One B-rep face of a CAD part: STEP entity #61270.
In plain terms, the planar face has unit normal (0, 0, -1).
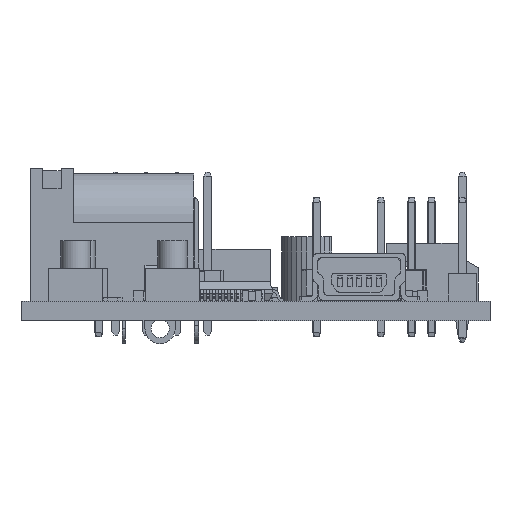
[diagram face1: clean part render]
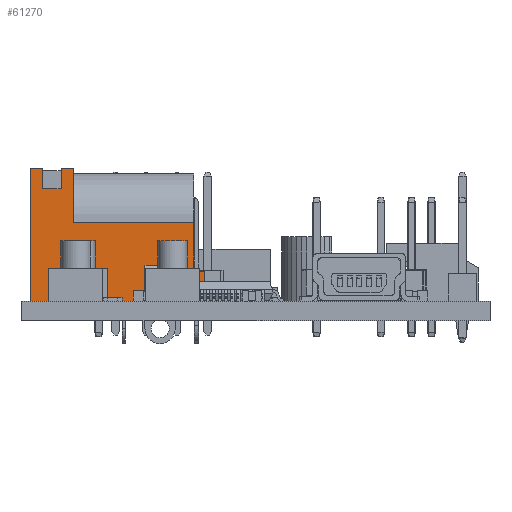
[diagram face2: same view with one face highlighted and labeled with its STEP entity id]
Its self-contained STEP definition (entity closure, numbers rounded to 3 decimals):
#61107 = VERTEX_POINT('',#61108);
#61108 = CARTESIAN_POINT('',(-14.4,-6.5,-4.5));
#61114 = EDGE_CURVE('',#61107,#61115,#61117,.T.);
#61115 = VERTEX_POINT('',#61116);
#61116 = CARTESIAN_POINT('',(-11.95,-6.5,-4.5));
#61117 = LINE('',#61118,#61119);
#61118 = CARTESIAN_POINT('',(-14.4,-6.5,-4.5));
#61119 = VECTOR('',#61120,1.);
#61120 = DIRECTION('',(1.,0.,0.));
#61123 = VERTEX_POINT('',#61124);
#61124 = CARTESIAN_POINT('',(-9.45,-6.5,-4.5));
#61130 = EDGE_CURVE('',#61123,#61131,#61133,.T.);
#61131 = VERTEX_POINT('',#61132);
#61132 = CARTESIAN_POINT('',(0.,-6.5,-4.5));
#61133 = LINE('',#61134,#61135);
#61134 = CARTESIAN_POINT('',(-14.4,-6.5,-4.5));
#61135 = VECTOR('',#61136,1.);
#61136 = DIRECTION('',(1.,0.,0.));
#61221 = VERTEX_POINT('',#61222);
#61222 = CARTESIAN_POINT('',(-13.5,-4.,-4.5));
#61228 = EDGE_CURVE('',#61221,#61229,#61231,.T.);
#61229 = VERTEX_POINT('',#61230);
#61230 = CARTESIAN_POINT('',(-14.4,-4.,-4.5));
#61231 = LINE('',#61232,#61233);
#61232 = CARTESIAN_POINT('',(-14.4,-4.,-4.5));
#61233 = VECTOR('',#61234,1.);
#61234 = DIRECTION('',(-1.,-0.,-0.));
#61270 = ADVANCED_FACE('',(#61271),#61374,.T.);
#61271 = FACE_BOUND('',#61272,.T.);
#61272 = EDGE_LOOP('',(#61273,#61274,#61282,#61290,#61296,#61297,#61303,
    #61304,#61312,#61320,#61328,#61336,#61344,#61352,#61360,#61368));
#61273 = ORIENTED_EDGE('',*,*,#61130,.F.);
#61274 = ORIENTED_EDGE('',*,*,#61275,.T.);
#61275 = EDGE_CURVE('',#61123,#61276,#61278,.T.);
#61276 = VERTEX_POINT('',#61277);
#61277 = CARTESIAN_POINT('',(-9.45,-3.5,-4.5));
#61278 = LINE('',#61279,#61280);
#61279 = CARTESIAN_POINT('',(-9.45,-10.,-4.5));
#61280 = VECTOR('',#61281,1.);
#61281 = DIRECTION('',(-0.,1.,-0.));
#61282 = ORIENTED_EDGE('',*,*,#61283,.T.);
#61283 = EDGE_CURVE('',#61276,#61284,#61286,.T.);
#61284 = VERTEX_POINT('',#61285);
#61285 = CARTESIAN_POINT('',(-11.95,-3.5,-4.5));
#61286 = LINE('',#61287,#61288);
#61287 = CARTESIAN_POINT('',(-11.95,-3.5,-4.5));
#61288 = VECTOR('',#61289,1.);
#61289 = DIRECTION('',(-1.,-0.,0.));
#61290 = ORIENTED_EDGE('',*,*,#61291,.F.);
#61291 = EDGE_CURVE('',#61115,#61284,#61292,.T.);
#61292 = LINE('',#61293,#61294);
#61293 = CARTESIAN_POINT('',(-11.95,-10.,-4.5));
#61294 = VECTOR('',#61295,1.);
#61295 = DIRECTION('',(-0.,1.,-0.));
#61296 = ORIENTED_EDGE('',*,*,#61114,.F.);
#61297 = ORIENTED_EDGE('',*,*,#61298,.T.);
#61298 = EDGE_CURVE('',#61107,#61229,#61299,.T.);
#61299 = LINE('',#61300,#61301);
#61300 = CARTESIAN_POINT('',(-14.4,4.5,-4.5));
#61301 = VECTOR('',#61302,1.);
#61302 = DIRECTION('',(-0.,1.,0.));
#61303 = ORIENTED_EDGE('',*,*,#61228,.F.);
#61304 = ORIENTED_EDGE('',*,*,#61305,.F.);
#61305 = EDGE_CURVE('',#61306,#61221,#61308,.T.);
#61306 = VERTEX_POINT('',#61307);
#61307 = CARTESIAN_POINT('',(-13.5,0.,-4.5));
#61308 = LINE('',#61309,#61310);
#61309 = CARTESIAN_POINT('',(-13.5,-4.,-4.5));
#61310 = VECTOR('',#61311,1.);
#61311 = DIRECTION('',(-0.,-1.,-0.));
#61312 = ORIENTED_EDGE('',*,*,#61313,.T.);
#61313 = EDGE_CURVE('',#61306,#61314,#61316,.T.);
#61314 = VERTEX_POINT('',#61315);
#61315 = CARTESIAN_POINT('',(-3.5,0.,-4.5));
#61316 = LINE('',#61317,#61318);
#61317 = CARTESIAN_POINT('',(-14.4,0.,-4.5));
#61318 = VECTOR('',#61319,1.);
#61319 = DIRECTION('',(1.,-0.,-0.));
#61320 = ORIENTED_EDGE('',*,*,#61321,.T.);
#61321 = EDGE_CURVE('',#61314,#61322,#61324,.T.);
#61322 = VERTEX_POINT('',#61323);
#61323 = CARTESIAN_POINT('',(-3.5,4.5,-4.5));
#61324 = LINE('',#61325,#61326);
#61325 = CARTESIAN_POINT('',(-3.5,0.,-4.5));
#61326 = VECTOR('',#61327,1.);
#61327 = DIRECTION('',(0.,1.,0.));
#61328 = ORIENTED_EDGE('',*,*,#61329,.T.);
#61329 = EDGE_CURVE('',#61322,#61330,#61332,.T.);
#61330 = VERTEX_POINT('',#61331);
#61331 = CARTESIAN_POINT('',(-2.5,4.5,-4.5));
#61332 = LINE('',#61333,#61334);
#61333 = CARTESIAN_POINT('',(-14.4,4.5,-4.5));
#61334 = VECTOR('',#61335,1.);
#61335 = DIRECTION('',(1.,0.,0.));
#61336 = ORIENTED_EDGE('',*,*,#61337,.F.);
#61337 = EDGE_CURVE('',#61338,#61330,#61340,.T.);
#61338 = VERTEX_POINT('',#61339);
#61339 = CARTESIAN_POINT('',(-2.5,2.8,-4.5));
#61340 = LINE('',#61341,#61342);
#61341 = CARTESIAN_POINT('',(-2.5,2.8,-4.5));
#61342 = VECTOR('',#61343,1.);
#61343 = DIRECTION('',(-0.,1.,0.));
#61344 = ORIENTED_EDGE('',*,*,#61345,.F.);
#61345 = EDGE_CURVE('',#61346,#61338,#61348,.T.);
#61346 = VERTEX_POINT('',#61347);
#61347 = CARTESIAN_POINT('',(-1.,2.8,-4.5));
#61348 = LINE('',#61349,#61350);
#61349 = CARTESIAN_POINT('',(-1.,2.8,-4.5));
#61350 = VECTOR('',#61351,1.);
#61351 = DIRECTION('',(-1.,0.,0.));
#61352 = ORIENTED_EDGE('',*,*,#61353,.T.);
#61353 = EDGE_CURVE('',#61346,#61354,#61356,.T.);
#61354 = VERTEX_POINT('',#61355);
#61355 = CARTESIAN_POINT('',(-1.,4.5,-4.5));
#61356 = LINE('',#61357,#61358);
#61357 = CARTESIAN_POINT('',(-1.,2.8,-4.5));
#61358 = VECTOR('',#61359,1.);
#61359 = DIRECTION('',(-0.,1.,0.));
#61360 = ORIENTED_EDGE('',*,*,#61361,.T.);
#61361 = EDGE_CURVE('',#61354,#61362,#61364,.T.);
#61362 = VERTEX_POINT('',#61363);
#61363 = CARTESIAN_POINT('',(0.,4.5,-4.5));
#61364 = LINE('',#61365,#61366);
#61365 = CARTESIAN_POINT('',(-14.4,4.5,-4.5));
#61366 = VECTOR('',#61367,1.);
#61367 = DIRECTION('',(1.,0.,0.));
#61368 = ORIENTED_EDGE('',*,*,#61369,.F.);
#61369 = EDGE_CURVE('',#61131,#61362,#61370,.T.);
#61370 = LINE('',#61371,#61372);
#61371 = CARTESIAN_POINT('',(0.,4.5,-4.5));
#61372 = VECTOR('',#61373,1.);
#61373 = DIRECTION('',(-0.,1.,0.));
#61374 = PLANE('',#61375);
#61375 = AXIS2_PLACEMENT_3D('',#61376,#61377,#61378);
#61376 = CARTESIAN_POINT('',(-14.4,4.5,-4.5));
#61377 = DIRECTION('',(0.,0.,-1.));
#61378 = DIRECTION('',(-1.,0.,0.));
